VERSION 5.7 ;
  NOWIREEXTENSIONATPIN ON ;
  DIVIDERCHAR "/" ;
  BUSBITCHARS "[]" ;
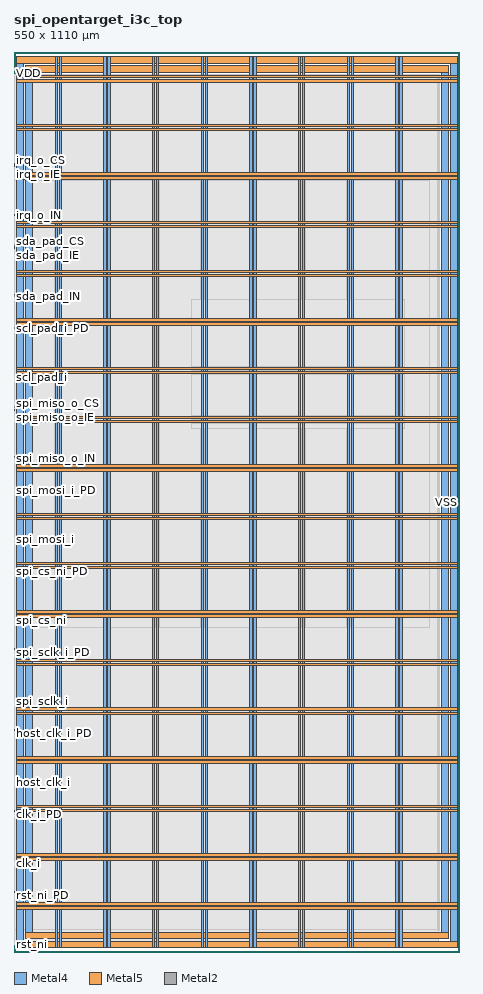
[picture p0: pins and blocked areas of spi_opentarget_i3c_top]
MACRO spi_opentarget_i3c_top
  CLASS BLOCK ;
  FOREIGN spi_opentarget_i3c_top ;
  ORIGIN 0.000 0.000 ;
  SIZE 550.000 BY 1110.000 ;
  PIN VDD
    DIRECTION INOUT ;
    USE POWER ;
    PORT
      LAYER Metal4 ;
        RECT 14.200 16.440 22.200 1092.920 ;
    END
    PORT
      LAYER Metal4 ;
        RECT 527.720 16.440 535.720 1092.920 ;
    END
    PORT
      LAYER Metal5 ;
        RECT 14.200 16.440 535.720 24.440 ;
    END
    PORT
      LAYER Metal5 ;
        RECT 14.200 1084.920 535.720 1092.920 ;
    END
    PORT
      LAYER Metal4 ;
        RECT 50.700 5.440 53.700 1103.920 ;
    END
    PORT
      LAYER Metal4 ;
        RECT 110.700 5.440 113.700 1103.920 ;
    END
    PORT
      LAYER Metal4 ;
        RECT 170.700 5.440 173.700 1103.920 ;
    END
    PORT
      LAYER Metal4 ;
        RECT 230.700 5.440 233.700 1103.920 ;
    END
    PORT
      LAYER Metal4 ;
        RECT 290.700 5.440 293.700 1103.920 ;
    END
    PORT
      LAYER Metal4 ;
        RECT 350.700 5.440 353.700 1103.920 ;
    END
    PORT
      LAYER Metal4 ;
        RECT 410.700 5.440 413.700 1103.920 ;
    END
    PORT
      LAYER Metal4 ;
        RECT 470.700 5.440 473.700 1103.920 ;
    END
    PORT
      LAYER Metal5 ;
        RECT 3.200 52.940 546.720 55.940 ;
    END
    PORT
      LAYER Metal5 ;
        RECT 3.200 112.940 546.720 115.940 ;
    END
    PORT
      LAYER Metal5 ;
        RECT 3.200 172.940 546.720 175.940 ;
    END
    PORT
      LAYER Metal5 ;
        RECT 3.200 232.940 546.720 235.940 ;
    END
    PORT
      LAYER Metal5 ;
        RECT 3.200 292.940 546.720 295.940 ;
    END
    PORT
      LAYER Metal5 ;
        RECT 3.200 352.940 546.720 355.940 ;
    END
    PORT
      LAYER Metal5 ;
        RECT 3.200 412.940 546.720 415.940 ;
    END
    PORT
      LAYER Metal5 ;
        RECT 3.200 472.940 546.720 475.940 ;
    END
    PORT
      LAYER Metal5 ;
        RECT 3.200 532.940 546.720 535.940 ;
    END
    PORT
      LAYER Metal5 ;
        RECT 3.200 592.940 546.720 595.940 ;
    END
    PORT
      LAYER Metal5 ;
        RECT 3.200 652.940 546.720 655.940 ;
    END
    PORT
      LAYER Metal5 ;
        RECT 3.200 712.940 546.720 715.940 ;
    END
    PORT
      LAYER Metal5 ;
        RECT 3.200 772.940 546.720 775.940 ;
    END
    PORT
      LAYER Metal5 ;
        RECT 3.200 832.940 546.720 835.940 ;
    END
    PORT
      LAYER Metal5 ;
        RECT 3.200 892.940 546.720 895.940 ;
    END
    PORT
      LAYER Metal5 ;
        RECT 3.200 952.940 546.720 955.940 ;
    END
    PORT
      LAYER Metal5 ;
        RECT 3.200 1012.940 546.720 1015.940 ;
    END
    PORT
      LAYER Metal5 ;
        RECT 3.200 1072.940 546.720 1075.940 ;
    END
  END VDD
  PIN VSS
    DIRECTION INOUT ;
    USE GROUND ;
    PORT
      LAYER Metal4 ;
        RECT 3.200 5.440 11.200 1103.920 ;
    END
    PORT
      LAYER Metal4 ;
        RECT 538.720 5.440 546.720 1103.920 ;
    END
    PORT
      LAYER Metal5 ;
        RECT 3.200 5.440 546.720 13.440 ;
    END
    PORT
      LAYER Metal5 ;
        RECT 3.200 1095.920 546.720 1103.920 ;
    END
    PORT
      LAYER Metal4 ;
        RECT 55.700 5.440 58.700 1103.920 ;
    END
    PORT
      LAYER Metal4 ;
        RECT 115.700 5.440 118.700 1103.920 ;
    END
    PORT
      LAYER Metal4 ;
        RECT 175.700 5.440 178.700 1103.920 ;
    END
    PORT
      LAYER Metal4 ;
        RECT 235.700 5.440 238.700 1103.920 ;
    END
    PORT
      LAYER Metal4 ;
        RECT 295.700 5.440 298.700 1103.920 ;
    END
    PORT
      LAYER Metal4 ;
        RECT 355.700 5.440 358.700 1103.920 ;
    END
    PORT
      LAYER Metal4 ;
        RECT 415.700 5.440 418.700 1103.920 ;
    END
    PORT
      LAYER Metal4 ;
        RECT 475.700 5.440 478.700 1103.920 ;
    END
    PORT
      LAYER Metal5 ;
        RECT 3.200 57.940 546.720 60.940 ;
    END
    PORT
      LAYER Metal5 ;
        RECT 3.200 117.940 546.720 120.940 ;
    END
    PORT
      LAYER Metal5 ;
        RECT 3.200 177.940 546.720 180.940 ;
    END
    PORT
      LAYER Metal5 ;
        RECT 3.200 237.940 546.720 240.940 ;
    END
    PORT
      LAYER Metal5 ;
        RECT 3.200 297.940 546.720 300.940 ;
    END
    PORT
      LAYER Metal5 ;
        RECT 3.200 357.940 546.720 360.940 ;
    END
    PORT
      LAYER Metal5 ;
        RECT 3.200 417.940 546.720 420.940 ;
    END
    PORT
      LAYER Metal5 ;
        RECT 3.200 477.940 546.720 480.940 ;
    END
    PORT
      LAYER Metal5 ;
        RECT 3.200 537.940 546.720 540.940 ;
    END
    PORT
      LAYER Metal5 ;
        RECT 3.200 597.940 546.720 600.940 ;
    END
    PORT
      LAYER Metal5 ;
        RECT 3.200 657.940 546.720 660.940 ;
    END
    PORT
      LAYER Metal5 ;
        RECT 3.200 717.940 546.720 720.940 ;
    END
    PORT
      LAYER Metal5 ;
        RECT 3.200 777.940 546.720 780.940 ;
    END
    PORT
      LAYER Metal5 ;
        RECT 3.200 837.940 546.720 840.940 ;
    END
    PORT
      LAYER Metal5 ;
        RECT 3.200 897.940 546.720 900.940 ;
    END
    PORT
      LAYER Metal5 ;
        RECT 3.200 957.940 546.720 960.940 ;
    END
    PORT
      LAYER Metal5 ;
        RECT 3.200 1017.940 546.720 1020.940 ;
    END
    PORT
      LAYER Metal5 ;
        RECT 3.200 1077.940 546.720 1080.940 ;
    END
  END VSS
  PIN clk_i
    DIRECTION INPUT ;
    USE SIGNAL ;
    ANTENNAGATEAREA 4.738000 ;
    PORT
      LAYER Metal2 ;
        RECT 0.000 108.760 1.000 109.140 ;
    END
  END clk_i
  PIN clk_i_PD
    DIRECTION OUTPUT ;
    USE SIGNAL ;
    ANTENNADIFFAREA 0.360800 ;
    PORT
      LAYER Metal2 ;
        RECT 0.000 169.290 1.000 169.670 ;
    END
  END clk_i_PD
  PIN clk_i_PU
    DIRECTION OUTPUT ;
    USE SIGNAL ;
    ANTENNADIFFAREA 0.360800 ;
    PORT
      LAYER Metal2 ;
        RECT 0.000 173.655 1.000 174.035 ;
    END
  END clk_i_PU
  PIN host_clk_i
    DIRECTION INPUT ;
    USE SIGNAL ;
    ANTENNAGATEAREA 4.738000 ;
    PORT
      LAYER Metal2 ;
        RECT 0.000 208.760 1.000 209.140 ;
    END
  END host_clk_i
  PIN host_clk_i_PD
    DIRECTION OUTPUT ;
    USE SIGNAL ;
    ANTENNADIFFAREA 0.360800 ;
    PORT
      LAYER Metal2 ;
        RECT 0.000 269.290 1.000 269.670 ;
    END
  END host_clk_i_PD
  PIN host_clk_i_PU
    DIRECTION OUTPUT ;
    USE SIGNAL ;
    ANTENNADIFFAREA 0.360800 ;
    PORT
      LAYER Metal2 ;
        RECT 0.000 273.655 1.000 274.035 ;
    END
  END host_clk_i_PU
  PIN irq_o_CS
    DIRECTION OUTPUT ;
    USE SIGNAL ;
    ANTENNADIFFAREA 0.360800 ;
    PORT
      LAYER Metal2 ;
        RECT 0.000 976.260 1.000 976.640 ;
    END
  END irq_o_CS
  PIN irq_o_IE
    DIRECTION OUTPUT ;
    USE SIGNAL ;
    ANTENNADIFFAREA 0.360800 ;
    PORT
      LAYER Metal2 ;
        RECT 0.000 968.235 1.000 968.615 ;
    END
  END irq_o_IE
  PIN irq_o_IN
    DIRECTION INPUT ;
    USE SIGNAL ;
    PORT
      LAYER Metal2 ;
        RECT 0.000 908.760 1.000 909.140 ;
    END
  END irq_o_IN
  PIN irq_o_OE
    DIRECTION OUTPUT ;
    USE SIGNAL ;
    ANTENNADIFFAREA 0.536800 ;
    PORT
      LAYER Metal2 ;
        RECT 0.000 909.490 1.000 909.870 ;
    END
  END irq_o_OE
  PIN irq_o_OUT
    DIRECTION OUTPUT ;
    USE SIGNAL ;
    ANTENNADIFFAREA 0.897600 ;
    PORT
      LAYER Metal2 ;
        RECT 0.000 910.220 1.000 910.600 ;
    END
  END irq_o_OUT
  PIN irq_o_PD
    DIRECTION OUTPUT ;
    USE SIGNAL ;
    ANTENNADIFFAREA 0.360800 ;
    PORT
      LAYER Metal2 ;
        RECT 0.000 969.290 1.000 969.670 ;
    END
  END irq_o_PD
  PIN irq_o_PDRV0
    DIRECTION OUTPUT ;
    USE SIGNAL ;
    ANTENNADIFFAREA 0.360800 ;
    PORT
      LAYER Metal2 ;
        RECT 0.000 972.510 1.000 972.890 ;
    END
  END irq_o_PDRV0
  PIN irq_o_PDRV1
    DIRECTION OUTPUT ;
    USE SIGNAL ;
    ANTENNADIFFAREA 0.360800 ;
    PORT
      LAYER Metal2 ;
        RECT 0.000 971.800 1.000 972.180 ;
    END
  END irq_o_PDRV1
  PIN irq_o_PU
    DIRECTION OUTPUT ;
    USE SIGNAL ;
    ANTENNADIFFAREA 0.360800 ;
    PORT
      LAYER Metal2 ;
        RECT 0.000 973.655 1.000 974.035 ;
    END
  END irq_o_PU
  PIN irq_o_SL
    DIRECTION OUTPUT ;
    USE SIGNAL ;
    ANTENNADIFFAREA 0.360800 ;
    PORT
      LAYER Metal2 ;
        RECT 0.000 910.950 1.000 911.330 ;
    END
  END irq_o_SL
  PIN rst_ni
    DIRECTION INPUT ;
    USE SIGNAL ;
    ANTENNAGATEAREA 0.396000 ;
    PORT
      LAYER Metal2 ;
        RECT 0.000 8.760 1.000 9.140 ;
    END
  END rst_ni
  PIN rst_ni_PD
    DIRECTION OUTPUT ;
    USE SIGNAL ;
    ANTENNADIFFAREA 0.360800 ;
    PORT
      LAYER Metal2 ;
        RECT 0.000 69.290 1.000 69.670 ;
    END
  END rst_ni_PD
  PIN rst_ni_PU
    DIRECTION OUTPUT ;
    USE SIGNAL ;
    ANTENNADIFFAREA 0.360800 ;
    PORT
      LAYER Metal2 ;
        RECT 0.000 73.655 1.000 74.035 ;
    END
  END rst_ni_PU
  PIN scl_pad_i
    DIRECTION INPUT ;
    USE SIGNAL ;
    ANTENNAGATEAREA 0.396000 ;
    PORT
      LAYER Metal2 ;
        RECT 0.000 708.760 1.000 709.140 ;
    END
  END scl_pad_i
  PIN scl_pad_i_PD
    DIRECTION OUTPUT ;
    USE SIGNAL ;
    ANTENNADIFFAREA 0.360800 ;
    PORT
      LAYER Metal2 ;
        RECT 0.000 769.290 1.000 769.670 ;
    END
  END scl_pad_i_PD
  PIN scl_pad_i_PU
    DIRECTION OUTPUT ;
    USE SIGNAL ;
    ANTENNADIFFAREA 0.360800 ;
    PORT
      LAYER Metal2 ;
        RECT 0.000 773.655 1.000 774.035 ;
    END
  END scl_pad_i_PU
  PIN sda_pad_CS
    DIRECTION OUTPUT ;
    USE SIGNAL ;
    ANTENNADIFFAREA 0.360800 ;
    PORT
      LAYER Metal2 ;
        RECT 0.000 876.260 1.000 876.640 ;
    END
  END sda_pad_CS
  PIN sda_pad_IE
    DIRECTION OUTPUT ;
    USE SIGNAL ;
    ANTENNADIFFAREA 0.536800 ;
    PORT
      LAYER Metal2 ;
        RECT 0.000 868.235 1.000 868.615 ;
    END
  END sda_pad_IE
  PIN sda_pad_IN
    DIRECTION INPUT ;
    USE SIGNAL ;
    ANTENNAGATEAREA 0.396000 ;
    PORT
      LAYER Metal2 ;
        RECT 0.000 808.760 1.000 809.140 ;
    END
  END sda_pad_IN
  PIN sda_pad_OUT
    DIRECTION OUTPUT ;
    USE SIGNAL ;
    ANTENNADIFFAREA 0.897600 ;
    PORT
      LAYER Metal2 ;
        RECT 0.000 810.220 1.000 810.600 ;
    END
  END sda_pad_OUT
  PIN sda_pad_PD
    DIRECTION OUTPUT ;
    USE SIGNAL ;
    ANTENNADIFFAREA 0.360800 ;
    PORT
      LAYER Metal2 ;
        RECT 0.000 869.290 1.000 869.670 ;
    END
  END sda_pad_PD
  PIN sda_pad_PDRV0
    DIRECTION OUTPUT ;
    USE SIGNAL ;
    ANTENNADIFFAREA 0.360800 ;
    PORT
      LAYER Metal2 ;
        RECT 0.000 872.510 1.000 872.890 ;
    END
  END sda_pad_PDRV0
  PIN sda_pad_PDRV1
    DIRECTION OUTPUT ;
    USE SIGNAL ;
    ANTENNADIFFAREA 0.360800 ;
    PORT
      LAYER Metal2 ;
        RECT 0.000 871.800 1.000 872.180 ;
    END
  END sda_pad_PDRV1
  PIN sda_pad_PU
    DIRECTION OUTPUT ;
    USE SIGNAL ;
    ANTENNADIFFAREA 0.360800 ;
    PORT
      LAYER Metal2 ;
        RECT 0.000 873.655 1.000 874.035 ;
    END
  END sda_pad_PU
  PIN sda_pad_SL
    DIRECTION OUTPUT ;
    USE SIGNAL ;
    ANTENNADIFFAREA 0.360800 ;
    PORT
      LAYER Metal2 ;
        RECT 0.000 810.950 1.000 811.330 ;
    END
  END sda_pad_SL
  PIN sda_pad_oe
    DIRECTION OUTPUT ;
    USE SIGNAL ;
    ANTENNADIFFAREA 0.897600 ;
    PORT
      LAYER Metal2 ;
        RECT 0.000 809.490 1.000 809.870 ;
    END
  END sda_pad_oe
  PIN spi_cs_ni
    DIRECTION INPUT ;
    USE SIGNAL ;
    ANTENNAGATEAREA 0.396000 ;
    PORT
      LAYER Metal2 ;
        RECT 0.000 408.760 1.000 409.140 ;
    END
  END spi_cs_ni
  PIN spi_cs_ni_PD
    DIRECTION OUTPUT ;
    USE SIGNAL ;
    ANTENNADIFFAREA 0.360800 ;
    PORT
      LAYER Metal2 ;
        RECT 0.000 469.290 1.000 469.670 ;
    END
  END spi_cs_ni_PD
  PIN spi_cs_ni_PU
    DIRECTION OUTPUT ;
    USE SIGNAL ;
    ANTENNADIFFAREA 0.360800 ;
    PORT
      LAYER Metal2 ;
        RECT 0.000 473.655 1.000 474.035 ;
    END
  END spi_cs_ni_PU
  PIN spi_miso_o_CS
    DIRECTION OUTPUT ;
    USE SIGNAL ;
    ANTENNADIFFAREA 0.360800 ;
    PORT
      LAYER Metal2 ;
        RECT 0.000 676.260 1.000 676.640 ;
    END
  END spi_miso_o_CS
  PIN spi_miso_o_IE
    DIRECTION OUTPUT ;
    USE SIGNAL ;
    ANTENNADIFFAREA 0.360800 ;
    PORT
      LAYER Metal2 ;
        RECT 0.000 668.235 1.000 668.615 ;
    END
  END spi_miso_o_IE
  PIN spi_miso_o_IN
    DIRECTION INPUT ;
    USE SIGNAL ;
    PORT
      LAYER Metal2 ;
        RECT 0.000 608.760 1.000 609.140 ;
    END
  END spi_miso_o_IN
  PIN spi_miso_o_OE
    DIRECTION OUTPUT ;
    USE SIGNAL ;
    ANTENNADIFFAREA 0.536800 ;
    PORT
      LAYER Metal2 ;
        RECT 0.000 609.490 1.000 609.870 ;
    END
  END spi_miso_o_OE
  PIN spi_miso_o_OUT
    DIRECTION OUTPUT ;
    USE SIGNAL ;
    ANTENNADIFFAREA 0.897600 ;
    PORT
      LAYER Metal2 ;
        RECT 0.000 610.220 1.000 610.600 ;
    END
  END spi_miso_o_OUT
  PIN spi_miso_o_PD
    DIRECTION OUTPUT ;
    USE SIGNAL ;
    ANTENNADIFFAREA 0.360800 ;
    PORT
      LAYER Metal2 ;
        RECT 0.000 669.290 1.000 669.670 ;
    END
  END spi_miso_o_PD
  PIN spi_miso_o_PDRV0
    DIRECTION OUTPUT ;
    USE SIGNAL ;
    ANTENNADIFFAREA 0.360800 ;
    PORT
      LAYER Metal2 ;
        RECT 0.000 672.510 1.000 672.890 ;
    END
  END spi_miso_o_PDRV0
  PIN spi_miso_o_PDRV1
    DIRECTION OUTPUT ;
    USE SIGNAL ;
    ANTENNADIFFAREA 0.360800 ;
    PORT
      LAYER Metal2 ;
        RECT 0.000 671.800 1.000 672.180 ;
    END
  END spi_miso_o_PDRV1
  PIN spi_miso_o_PU
    DIRECTION OUTPUT ;
    USE SIGNAL ;
    ANTENNADIFFAREA 0.360800 ;
    PORT
      LAYER Metal2 ;
        RECT 0.000 673.655 1.000 674.035 ;
    END
  END spi_miso_o_PU
  PIN spi_miso_o_SL
    DIRECTION OUTPUT ;
    USE SIGNAL ;
    ANTENNADIFFAREA 0.360800 ;
    PORT
      LAYER Metal2 ;
        RECT 0.000 610.950 1.000 611.330 ;
    END
  END spi_miso_o_SL
  PIN spi_mosi_i
    DIRECTION INPUT ;
    USE SIGNAL ;
    ANTENNAGATEAREA 0.396000 ;
    PORT
      LAYER Metal2 ;
        RECT 0.000 508.760 1.000 509.140 ;
    END
  END spi_mosi_i
  PIN spi_mosi_i_PD
    DIRECTION OUTPUT ;
    USE SIGNAL ;
    ANTENNADIFFAREA 0.360800 ;
    PORT
      LAYER Metal2 ;
        RECT 0.000 569.290 1.000 569.670 ;
    END
  END spi_mosi_i_PD
  PIN spi_mosi_i_PU
    DIRECTION OUTPUT ;
    USE SIGNAL ;
    ANTENNADIFFAREA 0.360800 ;
    PORT
      LAYER Metal2 ;
        RECT 0.000 573.655 1.000 574.035 ;
    END
  END spi_mosi_i_PU
  PIN spi_sclk_i
    DIRECTION INPUT ;
    USE SIGNAL ;
    ANTENNAGATEAREA 0.606000 ;
    PORT
      LAYER Metal2 ;
        RECT 0.000 308.760 1.000 309.140 ;
    END
  END spi_sclk_i
  PIN spi_sclk_i_PD
    DIRECTION OUTPUT ;
    USE SIGNAL ;
    ANTENNADIFFAREA 0.360800 ;
    PORT
      LAYER Metal2 ;
        RECT 0.000 369.290 1.000 369.670 ;
    END
  END spi_sclk_i_PD
  PIN spi_sclk_i_PU
    DIRECTION OUTPUT ;
    USE SIGNAL ;
    ANTENNADIFFAREA 0.360800 ;
    PORT
      LAYER Metal2 ;
        RECT 0.000 373.655 1.000 374.035 ;
    END
  END spi_sclk_i_PU
  OBS
      LAYER Nwell ;
        RECT 24.770 27.010 525.150 1082.350 ;
      LAYER Metal1 ;
        RECT 25.200 27.140 524.720 1082.220 ;
      LAYER Metal2 ;
        RECT 0.140 976.940 523.460 1082.110 ;
        RECT 1.300 975.960 523.460 976.940 ;
        RECT 0.140 974.335 523.460 975.960 ;
        RECT 1.300 973.355 523.460 974.335 ;
        RECT 0.140 973.190 523.460 973.355 ;
        RECT 1.300 971.500 523.460 973.190 ;
        RECT 0.140 969.970 523.460 971.500 ;
        RECT 1.300 968.990 523.460 969.970 ;
        RECT 0.140 968.915 523.460 968.990 ;
        RECT 1.300 967.935 523.460 968.915 ;
        RECT 0.140 911.630 523.460 967.935 ;
        RECT 1.300 908.460 523.460 911.630 ;
        RECT 0.140 876.940 523.460 908.460 ;
        RECT 1.300 875.960 523.460 876.940 ;
        RECT 0.140 874.335 523.460 875.960 ;
        RECT 1.300 873.355 523.460 874.335 ;
        RECT 0.140 873.190 523.460 873.355 ;
        RECT 1.300 871.500 523.460 873.190 ;
        RECT 0.140 869.970 523.460 871.500 ;
        RECT 1.300 868.990 523.460 869.970 ;
        RECT 0.140 868.915 523.460 868.990 ;
        RECT 1.300 867.935 523.460 868.915 ;
        RECT 0.140 811.630 523.460 867.935 ;
        RECT 1.300 808.460 523.460 811.630 ;
        RECT 0.140 774.335 523.460 808.460 ;
        RECT 1.300 773.355 523.460 774.335 ;
        RECT 0.140 769.970 523.460 773.355 ;
        RECT 1.300 768.990 523.460 769.970 ;
        RECT 0.140 709.440 523.460 768.990 ;
        RECT 1.300 708.460 523.460 709.440 ;
        RECT 0.140 676.940 523.460 708.460 ;
        RECT 1.300 675.960 523.460 676.940 ;
        RECT 0.140 674.335 523.460 675.960 ;
        RECT 1.300 673.355 523.460 674.335 ;
        RECT 0.140 673.190 523.460 673.355 ;
        RECT 1.300 671.500 523.460 673.190 ;
        RECT 0.140 669.970 523.460 671.500 ;
        RECT 1.300 668.990 523.460 669.970 ;
        RECT 0.140 668.915 523.460 668.990 ;
        RECT 1.300 667.935 523.460 668.915 ;
        RECT 0.140 611.630 523.460 667.935 ;
        RECT 1.300 608.460 523.460 611.630 ;
        RECT 0.140 574.335 523.460 608.460 ;
        RECT 1.300 573.355 523.460 574.335 ;
        RECT 0.140 569.970 523.460 573.355 ;
        RECT 1.300 568.990 523.460 569.970 ;
        RECT 0.140 509.440 523.460 568.990 ;
        RECT 1.300 508.460 523.460 509.440 ;
        RECT 0.140 474.335 523.460 508.460 ;
        RECT 1.300 473.355 523.460 474.335 ;
        RECT 0.140 469.970 523.460 473.355 ;
        RECT 1.300 468.990 523.460 469.970 ;
        RECT 0.140 409.440 523.460 468.990 ;
        RECT 1.300 408.460 523.460 409.440 ;
        RECT 0.140 374.335 523.460 408.460 ;
        RECT 1.300 373.355 523.460 374.335 ;
        RECT 0.140 369.970 523.460 373.355 ;
        RECT 1.300 368.990 523.460 369.970 ;
        RECT 0.140 309.440 523.460 368.990 ;
        RECT 1.300 308.460 523.460 309.440 ;
        RECT 0.140 274.335 523.460 308.460 ;
        RECT 1.300 273.355 523.460 274.335 ;
        RECT 0.140 269.970 523.460 273.355 ;
        RECT 1.300 268.990 523.460 269.970 ;
        RECT 0.140 209.440 523.460 268.990 ;
        RECT 1.300 208.460 523.460 209.440 ;
        RECT 0.140 174.335 523.460 208.460 ;
        RECT 1.300 173.355 523.460 174.335 ;
        RECT 0.140 169.970 523.460 173.355 ;
        RECT 1.300 168.990 523.460 169.970 ;
        RECT 0.140 109.440 523.460 168.990 ;
        RECT 1.300 108.460 523.460 109.440 ;
        RECT 0.140 74.335 523.460 108.460 ;
        RECT 1.300 73.355 523.460 74.335 ;
        RECT 0.140 69.970 523.460 73.355 ;
        RECT 1.300 68.990 523.460 69.970 ;
        RECT 0.140 9.440 523.460 68.990 ;
        RECT 1.300 9.140 523.460 9.440 ;
      LAYER Metal3 ;
        RECT 0.090 27.300 522.390 1082.060 ;
      LAYER Metal4 ;
        RECT 0.140 400.490 2.900 951.910 ;
        RECT 11.500 400.490 13.900 951.910 ;
        RECT 22.500 400.490 50.400 951.910 ;
        RECT 54.000 400.490 55.400 951.910 ;
        RECT 59.000 400.490 110.400 951.910 ;
        RECT 114.000 400.490 115.400 951.910 ;
        RECT 119.000 400.490 170.400 951.910 ;
        RECT 174.000 400.490 175.400 951.910 ;
        RECT 179.000 400.490 230.400 951.910 ;
        RECT 234.000 400.490 235.400 951.910 ;
        RECT 239.000 400.490 290.400 951.910 ;
        RECT 294.000 400.490 295.400 951.910 ;
        RECT 299.000 400.490 350.400 951.910 ;
        RECT 354.000 400.490 355.400 951.910 ;
        RECT 359.000 400.490 410.400 951.910 ;
        RECT 414.000 400.490 415.400 951.910 ;
        RECT 419.000 400.490 470.400 951.910 ;
        RECT 474.000 400.490 475.400 951.910 ;
        RECT 479.000 400.490 512.260 951.910 ;
      LAYER Metal5 ;
        RECT 218.460 781.540 481.540 805.270 ;
        RECT 218.460 776.540 481.540 777.340 ;
        RECT 218.460 721.540 481.540 772.340 ;
        RECT 218.460 716.540 481.540 717.340 ;
        RECT 218.460 661.540 481.540 712.340 ;
        RECT 218.460 656.540 481.540 657.340 ;
        RECT 218.460 645.530 481.540 652.340 ;
  END
END spi_opentarget_i3c_top
END LIBRARY

